One B-rep face of a CAD part: STEP entity #1269.
In plain terms, the planar face has unit normal (1, 0, 0).
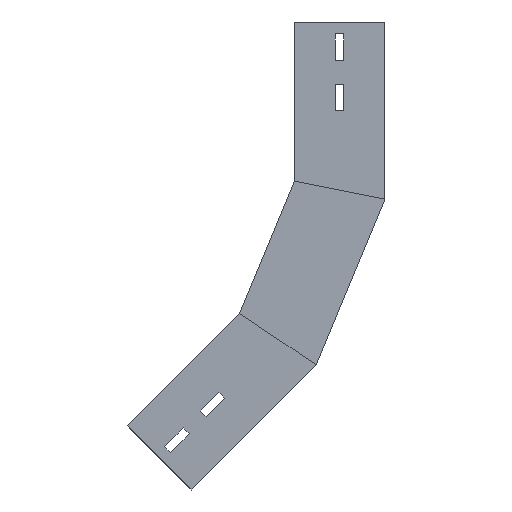
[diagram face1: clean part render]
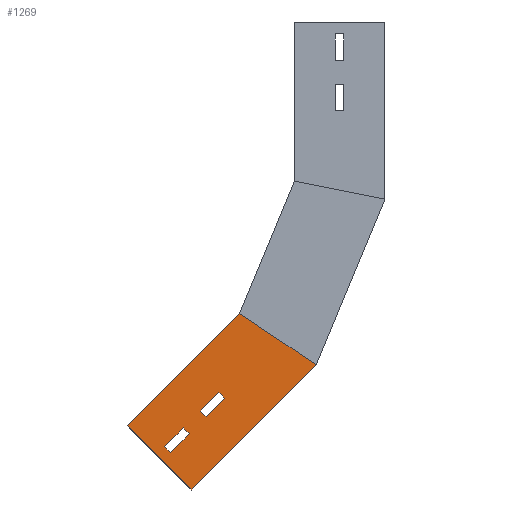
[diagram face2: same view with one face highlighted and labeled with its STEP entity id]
Its self-contained STEP definition (entity closure, numbers rounded to 3 decimals):
#23 = VECTOR ( 'NONE', #62, 1000. ) ;
#25 = VERTEX_POINT ( 'NONE', #623 ) ;
#26 = EDGE_CURVE ( 'NONE', #1308, #25, #164, .T. ) ;
#38 = PLANE ( 'NONE',  #137 ) ;
#55 = CARTESIAN_POINT ( 'NONE',  ( 0., 0., 0. ) ) ;
#62 = DIRECTION ( 'NONE',  ( 0., -1., 0. ) ) ;
#99 = VERTEX_POINT ( 'NONE', #1153 ) ;
#112 = VECTOR ( 'NONE', #212, 1000. ) ;
#137 = AXIS2_PLACEMENT_3D ( 'NONE', #55, #1238, #786 ) ;
#147 = VERTEX_POINT ( 'NONE', #323 ) ;
#151 = EDGE_CURVE ( 'NONE', #1207, #1392, #788, .T. ) ;
#153 = FACE_OUTER_BOUND ( 'NONE', #907, .T. ) ;
#164 = LINE ( 'NONE', #516, #851 ) ;
#170 = CARTESIAN_POINT ( 'NONE',  ( 0., 34., -73.505 ) ) ;
#179 = CARTESIAN_POINT ( 'NONE',  ( 0., 41., -73.505 ) ) ;
#190 = VECTOR ( 'NONE', #1244, 1000. ) ;
#192 = VECTOR ( 'NONE', #973, 1000. ) ;
#198 = LINE ( 'NONE', #179, #23 ) ;
#204 = CARTESIAN_POINT ( 'NONE',  ( 0., 41., -9.835 ) ) ;
#212 = DIRECTION ( 'NONE',  ( 0., 0., -1. ) ) ;
#238 = ORIENTED_EDGE ( 'NONE', *, *, #1084, .T. ) ;
#252 = CARTESIAN_POINT ( 'NONE',  ( 0., 34., -51.505 ) ) ;
#262 = LINE ( 'NONE', #1048, #1234 ) ;
#274 = VERTEX_POINT ( 'NONE', #1242 ) ;
#292 = ORIENTED_EDGE ( 'NONE', *, *, #596, .F. ) ;
#321 = LINE ( 'NONE', #1491, #190 ) ;
#323 = CARTESIAN_POINT ( 'NONE',  ( 0., 75., -131.682 ) ) ;
#328 = LINE ( 'NONE', #204, #344 ) ;
#344 = VECTOR ( 'NONE', #873, 1000. ) ;
#368 = VERTEX_POINT ( 'NONE', #1158 ) ;
#374 = EDGE_CURVE ( 'NONE', #1422, #1148, #811, .T. ) ;
#378 = LINE ( 'NONE', #740, #1086 ) ;
#413 = VECTOR ( 'NONE', #781, 1000. ) ;
#455 = EDGE_CURVE ( 'NONE', #1036, #368, #378, .T. ) ;
#474 = CARTESIAN_POINT ( 'NONE',  ( 0., 41., -51.505 ) ) ;
#486 = CARTESIAN_POINT ( 'NONE',  ( 0., 0., 0. ) ) ;
#507 = VECTOR ( 'NONE', #575, 1000. ) ;
#516 = CARTESIAN_POINT ( 'NONE',  ( 0., 41., -31.835 ) ) ;
#529 = VECTOR ( 'NONE', #1459, 1000. ) ;
#575 = DIRECTION ( 'NONE',  ( 0., 1., 0. ) ) ;
#596 = EDGE_CURVE ( 'NONE', #1036, #810, #1089, .T. ) ;
#603 = EDGE_LOOP ( 'NONE', ( #825, #238, #1296, #1283 ) ) ;
#608 = LINE ( 'NONE', #474, #112 ) ;
#618 = FACE_BOUND ( 'NONE', #1009, .T. ) ;
#623 = CARTESIAN_POINT ( 'NONE',  ( 0., 34., -31.835 ) ) ;
#627 = FACE_BOUND ( 'NONE', #603, .T. ) ;
#674 = VECTOR ( 'NONE', #1440, 1000. ) ;
#685 = CARTESIAN_POINT ( 'NONE',  ( 0., 41., -9.835 ) ) ;
#740 = CARTESIAN_POINT ( 'NONE',  ( 0., 0., 0. ) ) ;
#781 = DIRECTION ( 'NONE',  ( 0., -0.981, -0.195 ) ) ;
#786 = DIRECTION ( 'NONE',  ( 0., 0., 1. ) ) ;
#788 = LINE ( 'NONE', #1246, #674 ) ;
#797 = ORIENTED_EDGE ( 'NONE', *, *, #932, .F. ) ;
#810 = VERTEX_POINT ( 'NONE', #913 ) ;
#811 = LINE ( 'NONE', #685, #507 ) ;
#813 = CARTESIAN_POINT ( 'NONE',  ( 0., 41., -9.835 ) ) ;
#825 = ORIENTED_EDGE ( 'NONE', *, *, #1190, .T. ) ;
#836 = ORIENTED_EDGE ( 'NONE', *, *, #26, .T. ) ;
#846 = EDGE_CURVE ( 'NONE', #25, #1422, #321, .T. ) ;
#851 = VECTOR ( 'NONE', #977, 1000. ) ;
#858 = ORIENTED_EDGE ( 'NONE', *, *, #1311, .T. ) ;
#863 = LINE ( 'NONE', #1306, #192 ) ;
#873 = DIRECTION ( 'NONE',  ( 0., 0., -1. ) ) ;
#881 = CARTESIAN_POINT ( 'NONE',  ( 0., 41., -31.835 ) ) ;
#907 = EDGE_LOOP ( 'NONE', ( #956, #292, #1277, #797 ) ) ;
#913 = CARTESIAN_POINT ( 'NONE',  ( 0., 75., 0. ) ) ;
#932 = EDGE_CURVE ( 'NONE', #147, #368, #1465, .T. ) ;
#956 = ORIENTED_EDGE ( 'NONE', *, *, #1059, .F. ) ;
#973 = DIRECTION ( 'NONE',  ( 0., 1., 0. ) ) ;
#977 = DIRECTION ( 'NONE',  ( 0., -1., 0. ) ) ;
#1009 = EDGE_LOOP ( 'NONE', ( #1129, #858, #836, #1400 ) ) ;
#1036 = VERTEX_POINT ( 'NONE', #486 ) ;
#1048 = CARTESIAN_POINT ( 'NONE',  ( 0., 75., 0. ) ) ;
#1059 = EDGE_CURVE ( 'NONE', #810, #147, #262, .T. ) ;
#1084 = EDGE_CURVE ( 'NONE', #99, #274, #608, .T. ) ;
#1086 = VECTOR ( 'NONE', #1297, 1000. ) ;
#1089 = LINE ( 'NONE', #1466, #529 ) ;
#1129 = ORIENTED_EDGE ( 'NONE', *, *, #374, .T. ) ;
#1148 = VERTEX_POINT ( 'NONE', #813 ) ;
#1150 = CARTESIAN_POINT ( 'NONE',  ( 0., 34., -9.835 ) ) ;
#1153 = CARTESIAN_POINT ( 'NONE',  ( 0., 41., -51.505 ) ) ;
#1158 = CARTESIAN_POINT ( 'NONE',  ( 0., 0., -146.6 ) ) ;
#1189 = DIRECTION ( 'NONE',  ( 0., 0., -1. ) ) ;
#1190 = EDGE_CURVE ( 'NONE', #1392, #99, #863, .T. ) ;
#1207 = VERTEX_POINT ( 'NONE', #170 ) ;
#1234 = VECTOR ( 'NONE', #1189, 1000. ) ;
#1238 = DIRECTION ( 'NONE',  ( -1., 0., 0. ) ) ;
#1242 = CARTESIAN_POINT ( 'NONE',  ( 0., 41., -73.505 ) ) ;
#1244 = DIRECTION ( 'NONE',  ( 0., 0., 1. ) ) ;
#1246 = CARTESIAN_POINT ( 'NONE',  ( 0., 34., -51.505 ) ) ;
#1269 = ADVANCED_FACE ( 'NONE', ( #627, #153, #618 ), #38, .F. ) ;
#1277 = ORIENTED_EDGE ( 'NONE', *, *, #455, .T. ) ;
#1283 = ORIENTED_EDGE ( 'NONE', *, *, #151, .T. ) ;
#1296 = ORIENTED_EDGE ( 'NONE', *, *, #1356, .T. ) ;
#1297 = DIRECTION ( 'NONE',  ( 0., 0., -1. ) ) ;
#1306 = CARTESIAN_POINT ( 'NONE',  ( 0., 41., -51.505 ) ) ;
#1308 = VERTEX_POINT ( 'NONE', #881 ) ;
#1311 = EDGE_CURVE ( 'NONE', #1148, #1308, #328, .T. ) ;
#1356 = EDGE_CURVE ( 'NONE', #274, #1207, #198, .T. ) ;
#1364 = CARTESIAN_POINT ( 'NONE',  ( 0., 28.051, -141.02 ) ) ;
#1392 = VERTEX_POINT ( 'NONE', #252 ) ;
#1400 = ORIENTED_EDGE ( 'NONE', *, *, #846, .T. ) ;
#1422 = VERTEX_POINT ( 'NONE', #1150 ) ;
#1440 = DIRECTION ( 'NONE',  ( 0., 0., 1. ) ) ;
#1459 = DIRECTION ( 'NONE',  ( 0., 1., 0. ) ) ;
#1465 = LINE ( 'NONE', #1364, #413 ) ;
#1466 = CARTESIAN_POINT ( 'NONE',  ( 0., 0., 0. ) ) ;
#1491 = CARTESIAN_POINT ( 'NONE',  ( 0., 34., -9.835 ) ) ;
